# Generated by innovus_enablement/scripts/gen_fakeram.py: abstract 2048x39 SRAM.
# Geometry is an assumption (see script header), not PDK data.
VERSION 5.8 ;
BUSBITCHARS "[]" ;
DIVIDERCHAR "/" ;

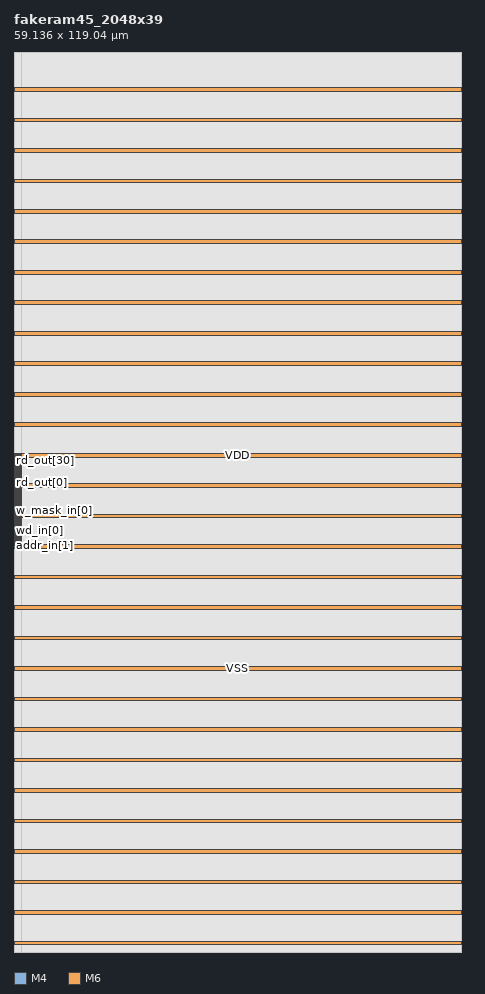
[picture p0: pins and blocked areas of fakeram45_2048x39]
MACRO fakeram45_2048x39
  CLASS BLOCK ;
  FOREIGN fakeram45_2048x39 0 0 ;
  ORIGIN 0 0 ;
  SIZE 59.1360 BY 119.0400 ;
  SYMMETRY X Y R90 ;
  PIN clk
    DIRECTION INPUT ;
    USE CLOCK ;
    PORT
      LAYER M4 ;
        RECT 0 53.3040 0.9600 53.3520 ;
    END
  END clk
  PIN ce_in
    DIRECTION INPUT ;
    USE SIGNAL ;
    PORT
      LAYER M4 ;
        RECT 0 53.4000 0.9600 53.4480 ;
    END
  END ce_in
  PIN we_in
    DIRECTION INPUT ;
    USE SIGNAL ;
    PORT
      LAYER M4 ;
        RECT 0 53.4960 0.9600 53.5440 ;
    END
  END we_in
  PIN addr_in[0]
    DIRECTION INPUT ;
    USE SIGNAL ;
    PORT
      LAYER M4 ;
        RECT 0 53.5920 0.9600 53.6400 ;
    END
  END addr_in[0]
  PIN addr_in[1]
    DIRECTION INPUT ;
    USE SIGNAL ;
    PORT
      LAYER M4 ;
        RECT 0 53.6880 0.9600 53.7360 ;
    END
  END addr_in[1]
  PIN addr_in[2]
    DIRECTION INPUT ;
    USE SIGNAL ;
    PORT
      LAYER M4 ;
        RECT 0 53.7840 0.9600 53.8320 ;
    END
  END addr_in[2]
  PIN addr_in[3]
    DIRECTION INPUT ;
    USE SIGNAL ;
    PORT
      LAYER M4 ;
        RECT 0 53.8800 0.9600 53.9280 ;
    END
  END addr_in[3]
  PIN addr_in[4]
    DIRECTION INPUT ;
    USE SIGNAL ;
    PORT
      LAYER M4 ;
        RECT 0 53.9760 0.9600 54.0240 ;
    END
  END addr_in[4]
  PIN addr_in[5]
    DIRECTION INPUT ;
    USE SIGNAL ;
    PORT
      LAYER M4 ;
        RECT 0 54.0720 0.9600 54.1200 ;
    END
  END addr_in[5]
  PIN addr_in[6]
    DIRECTION INPUT ;
    USE SIGNAL ;
    PORT
      LAYER M4 ;
        RECT 0 54.1680 0.9600 54.2160 ;
    END
  END addr_in[6]
  PIN addr_in[7]
    DIRECTION INPUT ;
    USE SIGNAL ;
    PORT
      LAYER M4 ;
        RECT 0 54.2640 0.9600 54.3120 ;
    END
  END addr_in[7]
  PIN addr_in[8]
    DIRECTION INPUT ;
    USE SIGNAL ;
    PORT
      LAYER M4 ;
        RECT 0 54.3600 0.9600 54.4080 ;
    END
  END addr_in[8]
  PIN addr_in[9]
    DIRECTION INPUT ;
    USE SIGNAL ;
    PORT
      LAYER M4 ;
        RECT 0 54.4560 0.9600 54.5040 ;
    END
  END addr_in[9]
  PIN addr_in[10]
    DIRECTION INPUT ;
    USE SIGNAL ;
    PORT
      LAYER M4 ;
        RECT 0 54.5520 0.9600 54.6000 ;
    END
  END addr_in[10]
  PIN wd_in[0]
    DIRECTION INPUT ;
    USE SIGNAL ;
    PORT
      LAYER M4 ;
        RECT 0 54.6480 0.9600 54.6960 ;
    END
  END wd_in[0]
  PIN wd_in[1]
    DIRECTION INPUT ;
    USE SIGNAL ;
    PORT
      LAYER M4 ;
        RECT 0 54.7440 0.9600 54.7920 ;
    END
  END wd_in[1]
  PIN wd_in[2]
    DIRECTION INPUT ;
    USE SIGNAL ;
    PORT
      LAYER M4 ;
        RECT 0 54.8400 0.9600 54.8880 ;
    END
  END wd_in[2]
  PIN wd_in[3]
    DIRECTION INPUT ;
    USE SIGNAL ;
    PORT
      LAYER M4 ;
        RECT 0 54.9360 0.9600 54.9840 ;
    END
  END wd_in[3]
  PIN wd_in[4]
    DIRECTION INPUT ;
    USE SIGNAL ;
    PORT
      LAYER M4 ;
        RECT 0 55.0320 0.9600 55.0800 ;
    END
  END wd_in[4]
  PIN wd_in[5]
    DIRECTION INPUT ;
    USE SIGNAL ;
    PORT
      LAYER M4 ;
        RECT 0 55.1280 0.9600 55.1760 ;
    END
  END wd_in[5]
  PIN wd_in[6]
    DIRECTION INPUT ;
    USE SIGNAL ;
    PORT
      LAYER M4 ;
        RECT 0 55.2240 0.9600 55.2720 ;
    END
  END wd_in[6]
  PIN wd_in[7]
    DIRECTION INPUT ;
    USE SIGNAL ;
    PORT
      LAYER M4 ;
        RECT 0 55.3200 0.9600 55.3680 ;
    END
  END wd_in[7]
  PIN wd_in[8]
    DIRECTION INPUT ;
    USE SIGNAL ;
    PORT
      LAYER M4 ;
        RECT 0 55.4160 0.9600 55.4640 ;
    END
  END wd_in[8]
  PIN wd_in[9]
    DIRECTION INPUT ;
    USE SIGNAL ;
    PORT
      LAYER M4 ;
        RECT 0 55.5120 0.9600 55.5600 ;
    END
  END wd_in[9]
  PIN wd_in[10]
    DIRECTION INPUT ;
    USE SIGNAL ;
    PORT
      LAYER M4 ;
        RECT 0 55.6080 0.9600 55.6560 ;
    END
  END wd_in[10]
  PIN wd_in[11]
    DIRECTION INPUT ;
    USE SIGNAL ;
    PORT
      LAYER M4 ;
        RECT 0 55.7040 0.9600 55.7520 ;
    END
  END wd_in[11]
  PIN wd_in[12]
    DIRECTION INPUT ;
    USE SIGNAL ;
    PORT
      LAYER M4 ;
        RECT 0 55.8000 0.9600 55.8480 ;
    END
  END wd_in[12]
  PIN wd_in[13]
    DIRECTION INPUT ;
    USE SIGNAL ;
    PORT
      LAYER M4 ;
        RECT 0 55.8960 0.9600 55.9440 ;
    END
  END wd_in[13]
  PIN wd_in[14]
    DIRECTION INPUT ;
    USE SIGNAL ;
    PORT
      LAYER M4 ;
        RECT 0 55.9920 0.9600 56.0400 ;
    END
  END wd_in[14]
  PIN wd_in[15]
    DIRECTION INPUT ;
    USE SIGNAL ;
    PORT
      LAYER M4 ;
        RECT 0 56.0880 0.9600 56.1360 ;
    END
  END wd_in[15]
  PIN wd_in[16]
    DIRECTION INPUT ;
    USE SIGNAL ;
    PORT
      LAYER M4 ;
        RECT 0 56.1840 0.9600 56.2320 ;
    END
  END wd_in[16]
  PIN wd_in[17]
    DIRECTION INPUT ;
    USE SIGNAL ;
    PORT
      LAYER M4 ;
        RECT 0 56.2800 0.9600 56.3280 ;
    END
  END wd_in[17]
  PIN wd_in[18]
    DIRECTION INPUT ;
    USE SIGNAL ;
    PORT
      LAYER M4 ;
        RECT 0 56.3760 0.9600 56.4240 ;
    END
  END wd_in[18]
  PIN wd_in[19]
    DIRECTION INPUT ;
    USE SIGNAL ;
    PORT
      LAYER M4 ;
        RECT 0 56.4720 0.9600 56.5200 ;
    END
  END wd_in[19]
  PIN wd_in[20]
    DIRECTION INPUT ;
    USE SIGNAL ;
    PORT
      LAYER M4 ;
        RECT 0 56.5680 0.9600 56.6160 ;
    END
  END wd_in[20]
  PIN wd_in[21]
    DIRECTION INPUT ;
    USE SIGNAL ;
    PORT
      LAYER M4 ;
        RECT 0 56.6640 0.9600 56.7120 ;
    END
  END wd_in[21]
  PIN wd_in[22]
    DIRECTION INPUT ;
    USE SIGNAL ;
    PORT
      LAYER M4 ;
        RECT 0 56.7600 0.9600 56.8080 ;
    END
  END wd_in[22]
  PIN wd_in[23]
    DIRECTION INPUT ;
    USE SIGNAL ;
    PORT
      LAYER M4 ;
        RECT 0 56.8560 0.9600 56.9040 ;
    END
  END wd_in[23]
  PIN wd_in[24]
    DIRECTION INPUT ;
    USE SIGNAL ;
    PORT
      LAYER M4 ;
        RECT 0 56.9520 0.9600 57.0000 ;
    END
  END wd_in[24]
  PIN wd_in[25]
    DIRECTION INPUT ;
    USE SIGNAL ;
    PORT
      LAYER M4 ;
        RECT 0 57.0480 0.9600 57.0960 ;
    END
  END wd_in[25]
  PIN wd_in[26]
    DIRECTION INPUT ;
    USE SIGNAL ;
    PORT
      LAYER M4 ;
        RECT 0 57.1440 0.9600 57.1920 ;
    END
  END wd_in[26]
  PIN wd_in[27]
    DIRECTION INPUT ;
    USE SIGNAL ;
    PORT
      LAYER M4 ;
        RECT 0 57.2400 0.9600 57.2880 ;
    END
  END wd_in[27]
  PIN wd_in[28]
    DIRECTION INPUT ;
    USE SIGNAL ;
    PORT
      LAYER M4 ;
        RECT 0 57.3360 0.9600 57.3840 ;
    END
  END wd_in[28]
  PIN wd_in[29]
    DIRECTION INPUT ;
    USE SIGNAL ;
    PORT
      LAYER M4 ;
        RECT 0 57.4320 0.9600 57.4800 ;
    END
  END wd_in[29]
  PIN wd_in[30]
    DIRECTION INPUT ;
    USE SIGNAL ;
    PORT
      LAYER M4 ;
        RECT 0 57.5280 0.9600 57.5760 ;
    END
  END wd_in[30]
  PIN wd_in[31]
    DIRECTION INPUT ;
    USE SIGNAL ;
    PORT
      LAYER M4 ;
        RECT 0 57.6240 0.9600 57.6720 ;
    END
  END wd_in[31]
  PIN wd_in[32]
    DIRECTION INPUT ;
    USE SIGNAL ;
    PORT
      LAYER M4 ;
        RECT 0 57.7200 0.9600 57.7680 ;
    END
  END wd_in[32]
  PIN wd_in[33]
    DIRECTION INPUT ;
    USE SIGNAL ;
    PORT
      LAYER M4 ;
        RECT 0 57.8160 0.9600 57.8640 ;
    END
  END wd_in[33]
  PIN wd_in[34]
    DIRECTION INPUT ;
    USE SIGNAL ;
    PORT
      LAYER M4 ;
        RECT 0 57.9120 0.9600 57.9600 ;
    END
  END wd_in[34]
  PIN wd_in[35]
    DIRECTION INPUT ;
    USE SIGNAL ;
    PORT
      LAYER M4 ;
        RECT 0 58.0080 0.9600 58.0560 ;
    END
  END wd_in[35]
  PIN wd_in[36]
    DIRECTION INPUT ;
    USE SIGNAL ;
    PORT
      LAYER M4 ;
        RECT 0 58.1040 0.9600 58.1520 ;
    END
  END wd_in[36]
  PIN wd_in[37]
    DIRECTION INPUT ;
    USE SIGNAL ;
    PORT
      LAYER M4 ;
        RECT 0 58.2000 0.9600 58.2480 ;
    END
  END wd_in[37]
  PIN wd_in[38]
    DIRECTION INPUT ;
    USE SIGNAL ;
    PORT
      LAYER M4 ;
        RECT 0 58.2960 0.9600 58.3440 ;
    END
  END wd_in[38]
  PIN w_mask_in[0]
    DIRECTION INPUT ;
    USE SIGNAL ;
    PORT
      LAYER M4 ;
        RECT 0 58.3920 0.9600 58.4400 ;
    END
  END w_mask_in[0]
  PIN w_mask_in[1]
    DIRECTION INPUT ;
    USE SIGNAL ;
    PORT
      LAYER M4 ;
        RECT 0 58.4880 0.9600 58.5360 ;
    END
  END w_mask_in[1]
  PIN w_mask_in[2]
    DIRECTION INPUT ;
    USE SIGNAL ;
    PORT
      LAYER M4 ;
        RECT 0 58.5840 0.9600 58.6320 ;
    END
  END w_mask_in[2]
  PIN w_mask_in[3]
    DIRECTION INPUT ;
    USE SIGNAL ;
    PORT
      LAYER M4 ;
        RECT 0 58.6800 0.9600 58.7280 ;
    END
  END w_mask_in[3]
  PIN w_mask_in[4]
    DIRECTION INPUT ;
    USE SIGNAL ;
    PORT
      LAYER M4 ;
        RECT 0 58.7760 0.9600 58.8240 ;
    END
  END w_mask_in[4]
  PIN w_mask_in[5]
    DIRECTION INPUT ;
    USE SIGNAL ;
    PORT
      LAYER M4 ;
        RECT 0 58.8720 0.9600 58.9200 ;
    END
  END w_mask_in[5]
  PIN w_mask_in[6]
    DIRECTION INPUT ;
    USE SIGNAL ;
    PORT
      LAYER M4 ;
        RECT 0 58.9680 0.9600 59.0160 ;
    END
  END w_mask_in[6]
  PIN w_mask_in[7]
    DIRECTION INPUT ;
    USE SIGNAL ;
    PORT
      LAYER M4 ;
        RECT 0 59.0640 0.9600 59.1120 ;
    END
  END w_mask_in[7]
  PIN w_mask_in[8]
    DIRECTION INPUT ;
    USE SIGNAL ;
    PORT
      LAYER M4 ;
        RECT 0 59.1600 0.9600 59.2080 ;
    END
  END w_mask_in[8]
  PIN w_mask_in[9]
    DIRECTION INPUT ;
    USE SIGNAL ;
    PORT
      LAYER M4 ;
        RECT 0 59.2560 0.9600 59.3040 ;
    END
  END w_mask_in[9]
  PIN w_mask_in[10]
    DIRECTION INPUT ;
    USE SIGNAL ;
    PORT
      LAYER M4 ;
        RECT 0 59.3520 0.9600 59.4000 ;
    END
  END w_mask_in[10]
  PIN w_mask_in[11]
    DIRECTION INPUT ;
    USE SIGNAL ;
    PORT
      LAYER M4 ;
        RECT 0 59.4480 0.9600 59.4960 ;
    END
  END w_mask_in[11]
  PIN w_mask_in[12]
    DIRECTION INPUT ;
    USE SIGNAL ;
    PORT
      LAYER M4 ;
        RECT 0 59.5440 0.9600 59.5920 ;
    END
  END w_mask_in[12]
  PIN w_mask_in[13]
    DIRECTION INPUT ;
    USE SIGNAL ;
    PORT
      LAYER M4 ;
        RECT 0 59.6400 0.9600 59.6880 ;
    END
  END w_mask_in[13]
  PIN w_mask_in[14]
    DIRECTION INPUT ;
    USE SIGNAL ;
    PORT
      LAYER M4 ;
        RECT 0 59.7360 0.9600 59.7840 ;
    END
  END w_mask_in[14]
  PIN w_mask_in[15]
    DIRECTION INPUT ;
    USE SIGNAL ;
    PORT
      LAYER M4 ;
        RECT 0 59.8320 0.9600 59.8800 ;
    END
  END w_mask_in[15]
  PIN w_mask_in[16]
    DIRECTION INPUT ;
    USE SIGNAL ;
    PORT
      LAYER M4 ;
        RECT 0 59.9280 0.9600 59.9760 ;
    END
  END w_mask_in[16]
  PIN w_mask_in[17]
    DIRECTION INPUT ;
    USE SIGNAL ;
    PORT
      LAYER M4 ;
        RECT 0 60.0240 0.9600 60.0720 ;
    END
  END w_mask_in[17]
  PIN w_mask_in[18]
    DIRECTION INPUT ;
    USE SIGNAL ;
    PORT
      LAYER M4 ;
        RECT 0 60.1200 0.9600 60.1680 ;
    END
  END w_mask_in[18]
  PIN w_mask_in[19]
    DIRECTION INPUT ;
    USE SIGNAL ;
    PORT
      LAYER M4 ;
        RECT 0 60.2160 0.9600 60.2640 ;
    END
  END w_mask_in[19]
  PIN w_mask_in[20]
    DIRECTION INPUT ;
    USE SIGNAL ;
    PORT
      LAYER M4 ;
        RECT 0 60.3120 0.9600 60.3600 ;
    END
  END w_mask_in[20]
  PIN w_mask_in[21]
    DIRECTION INPUT ;
    USE SIGNAL ;
    PORT
      LAYER M4 ;
        RECT 0 60.4080 0.9600 60.4560 ;
    END
  END w_mask_in[21]
  PIN w_mask_in[22]
    DIRECTION INPUT ;
    USE SIGNAL ;
    PORT
      LAYER M4 ;
        RECT 0 60.5040 0.9600 60.5520 ;
    END
  END w_mask_in[22]
  PIN w_mask_in[23]
    DIRECTION INPUT ;
    USE SIGNAL ;
    PORT
      LAYER M4 ;
        RECT 0 60.6000 0.9600 60.6480 ;
    END
  END w_mask_in[23]
  PIN w_mask_in[24]
    DIRECTION INPUT ;
    USE SIGNAL ;
    PORT
      LAYER M4 ;
        RECT 0 60.6960 0.9600 60.7440 ;
    END
  END w_mask_in[24]
  PIN w_mask_in[25]
    DIRECTION INPUT ;
    USE SIGNAL ;
    PORT
      LAYER M4 ;
        RECT 0 60.7920 0.9600 60.8400 ;
    END
  END w_mask_in[25]
  PIN w_mask_in[26]
    DIRECTION INPUT ;
    USE SIGNAL ;
    PORT
      LAYER M4 ;
        RECT 0 60.8880 0.9600 60.9360 ;
    END
  END w_mask_in[26]
  PIN w_mask_in[27]
    DIRECTION INPUT ;
    USE SIGNAL ;
    PORT
      LAYER M4 ;
        RECT 0 60.9840 0.9600 61.0320 ;
    END
  END w_mask_in[27]
  PIN w_mask_in[28]
    DIRECTION INPUT ;
    USE SIGNAL ;
    PORT
      LAYER M4 ;
        RECT 0 61.0800 0.9600 61.1280 ;
    END
  END w_mask_in[28]
  PIN w_mask_in[29]
    DIRECTION INPUT ;
    USE SIGNAL ;
    PORT
      LAYER M4 ;
        RECT 0 61.1760 0.9600 61.2240 ;
    END
  END w_mask_in[29]
  PIN w_mask_in[30]
    DIRECTION INPUT ;
    USE SIGNAL ;
    PORT
      LAYER M4 ;
        RECT 0 61.2720 0.9600 61.3200 ;
    END
  END w_mask_in[30]
  PIN w_mask_in[31]
    DIRECTION INPUT ;
    USE SIGNAL ;
    PORT
      LAYER M4 ;
        RECT 0 61.3680 0.9600 61.4160 ;
    END
  END w_mask_in[31]
  PIN w_mask_in[32]
    DIRECTION INPUT ;
    USE SIGNAL ;
    PORT
      LAYER M4 ;
        RECT 0 61.4640 0.9600 61.5120 ;
    END
  END w_mask_in[32]
  PIN w_mask_in[33]
    DIRECTION INPUT ;
    USE SIGNAL ;
    PORT
      LAYER M4 ;
        RECT 0 61.5600 0.9600 61.6080 ;
    END
  END w_mask_in[33]
  PIN w_mask_in[34]
    DIRECTION INPUT ;
    USE SIGNAL ;
    PORT
      LAYER M4 ;
        RECT 0 61.6560 0.9600 61.7040 ;
    END
  END w_mask_in[34]
  PIN w_mask_in[35]
    DIRECTION INPUT ;
    USE SIGNAL ;
    PORT
      LAYER M4 ;
        RECT 0 61.7520 0.9600 61.8000 ;
    END
  END w_mask_in[35]
  PIN w_mask_in[36]
    DIRECTION INPUT ;
    USE SIGNAL ;
    PORT
      LAYER M4 ;
        RECT 0 61.8480 0.9600 61.8960 ;
    END
  END w_mask_in[36]
  PIN w_mask_in[37]
    DIRECTION INPUT ;
    USE SIGNAL ;
    PORT
      LAYER M4 ;
        RECT 0 61.9440 0.9600 61.9920 ;
    END
  END w_mask_in[37]
  PIN w_mask_in[38]
    DIRECTION INPUT ;
    USE SIGNAL ;
    PORT
      LAYER M4 ;
        RECT 0 62.0400 0.9600 62.0880 ;
    END
  END w_mask_in[38]
  PIN rd_out[0]
    DIRECTION OUTPUT ;
    USE SIGNAL ;
    PORT
      LAYER M4 ;
        RECT 0 62.1360 0.9600 62.1840 ;
    END
  END rd_out[0]
  PIN rd_out[1]
    DIRECTION OUTPUT ;
    USE SIGNAL ;
    PORT
      LAYER M4 ;
        RECT 0 62.2320 0.9600 62.2800 ;
    END
  END rd_out[1]
  PIN rd_out[2]
    DIRECTION OUTPUT ;
    USE SIGNAL ;
    PORT
      LAYER M4 ;
        RECT 0 62.3280 0.9600 62.3760 ;
    END
  END rd_out[2]
  PIN rd_out[3]
    DIRECTION OUTPUT ;
    USE SIGNAL ;
    PORT
      LAYER M4 ;
        RECT 0 62.4240 0.9600 62.4720 ;
    END
  END rd_out[3]
  PIN rd_out[4]
    DIRECTION OUTPUT ;
    USE SIGNAL ;
    PORT
      LAYER M4 ;
        RECT 0 62.5200 0.9600 62.5680 ;
    END
  END rd_out[4]
  PIN rd_out[5]
    DIRECTION OUTPUT ;
    USE SIGNAL ;
    PORT
      LAYER M4 ;
        RECT 0 62.6160 0.9600 62.6640 ;
    END
  END rd_out[5]
  PIN rd_out[6]
    DIRECTION OUTPUT ;
    USE SIGNAL ;
    PORT
      LAYER M4 ;
        RECT 0 62.7120 0.9600 62.7600 ;
    END
  END rd_out[6]
  PIN rd_out[7]
    DIRECTION OUTPUT ;
    USE SIGNAL ;
    PORT
      LAYER M4 ;
        RECT 0 62.8080 0.9600 62.8560 ;
    END
  END rd_out[7]
  PIN rd_out[8]
    DIRECTION OUTPUT ;
    USE SIGNAL ;
    PORT
      LAYER M4 ;
        RECT 0 62.9040 0.9600 62.9520 ;
    END
  END rd_out[8]
  PIN rd_out[9]
    DIRECTION OUTPUT ;
    USE SIGNAL ;
    PORT
      LAYER M4 ;
        RECT 0 63.0000 0.9600 63.0480 ;
    END
  END rd_out[9]
  PIN rd_out[10]
    DIRECTION OUTPUT ;
    USE SIGNAL ;
    PORT
      LAYER M4 ;
        RECT 0 63.0960 0.9600 63.1440 ;
    END
  END rd_out[10]
  PIN rd_out[11]
    DIRECTION OUTPUT ;
    USE SIGNAL ;
    PORT
      LAYER M4 ;
        RECT 0 63.1920 0.9600 63.2400 ;
    END
  END rd_out[11]
  PIN rd_out[12]
    DIRECTION OUTPUT ;
    USE SIGNAL ;
    PORT
      LAYER M4 ;
        RECT 0 63.2880 0.9600 63.3360 ;
    END
  END rd_out[12]
  PIN rd_out[13]
    DIRECTION OUTPUT ;
    USE SIGNAL ;
    PORT
      LAYER M4 ;
        RECT 0 63.3840 0.9600 63.4320 ;
    END
  END rd_out[13]
  PIN rd_out[14]
    DIRECTION OUTPUT ;
    USE SIGNAL ;
    PORT
      LAYER M4 ;
        RECT 0 63.4800 0.9600 63.5280 ;
    END
  END rd_out[14]
  PIN rd_out[15]
    DIRECTION OUTPUT ;
    USE SIGNAL ;
    PORT
      LAYER M4 ;
        RECT 0 63.5760 0.9600 63.6240 ;
    END
  END rd_out[15]
  PIN rd_out[16]
    DIRECTION OUTPUT ;
    USE SIGNAL ;
    PORT
      LAYER M4 ;
        RECT 0 63.6720 0.9600 63.7200 ;
    END
  END rd_out[16]
  PIN rd_out[17]
    DIRECTION OUTPUT ;
    USE SIGNAL ;
    PORT
      LAYER M4 ;
        RECT 0 63.7680 0.9600 63.8160 ;
    END
  END rd_out[17]
  PIN rd_out[18]
    DIRECTION OUTPUT ;
    USE SIGNAL ;
    PORT
      LAYER M4 ;
        RECT 0 63.8640 0.9600 63.9120 ;
    END
  END rd_out[18]
  PIN rd_out[19]
    DIRECTION OUTPUT ;
    USE SIGNAL ;
    PORT
      LAYER M4 ;
        RECT 0 63.9600 0.9600 64.0080 ;
    END
  END rd_out[19]
  PIN rd_out[20]
    DIRECTION OUTPUT ;
    USE SIGNAL ;
    PORT
      LAYER M4 ;
        RECT 0 64.0560 0.9600 64.1040 ;
    END
  END rd_out[20]
  PIN rd_out[21]
    DIRECTION OUTPUT ;
    USE SIGNAL ;
    PORT
      LAYER M4 ;
        RECT 0 64.1520 0.9600 64.2000 ;
    END
  END rd_out[21]
  PIN rd_out[22]
    DIRECTION OUTPUT ;
    USE SIGNAL ;
    PORT
      LAYER M4 ;
        RECT 0 64.2480 0.9600 64.2960 ;
    END
  END rd_out[22]
  PIN rd_out[23]
    DIRECTION OUTPUT ;
    USE SIGNAL ;
    PORT
      LAYER M4 ;
        RECT 0 64.3440 0.9600 64.3920 ;
    END
  END rd_out[23]
  PIN rd_out[24]
    DIRECTION OUTPUT ;
    USE SIGNAL ;
    PORT
      LAYER M4 ;
        RECT 0 64.4400 0.9600 64.4880 ;
    END
  END rd_out[24]
  PIN rd_out[25]
    DIRECTION OUTPUT ;
    USE SIGNAL ;
    PORT
      LAYER M4 ;
        RECT 0 64.5360 0.9600 64.5840 ;
    END
  END rd_out[25]
  PIN rd_out[26]
    DIRECTION OUTPUT ;
    USE SIGNAL ;
    PORT
      LAYER M4 ;
        RECT 0 64.6320 0.9600 64.6800 ;
    END
  END rd_out[26]
  PIN rd_out[27]
    DIRECTION OUTPUT ;
    USE SIGNAL ;
    PORT
      LAYER M4 ;
        RECT 0 64.7280 0.9600 64.7760 ;
    END
  END rd_out[27]
  PIN rd_out[28]
    DIRECTION OUTPUT ;
    USE SIGNAL ;
    PORT
      LAYER M4 ;
        RECT 0 64.8240 0.9600 64.8720 ;
    END
  END rd_out[28]
  PIN rd_out[29]
    DIRECTION OUTPUT ;
    USE SIGNAL ;
    PORT
      LAYER M4 ;
        RECT 0 64.9200 0.9600 64.9680 ;
    END
  END rd_out[29]
  PIN rd_out[30]
    DIRECTION OUTPUT ;
    USE SIGNAL ;
    PORT
      LAYER M4 ;
        RECT 0 65.0160 0.9600 65.0640 ;
    END
  END rd_out[30]
  PIN rd_out[31]
    DIRECTION OUTPUT ;
    USE SIGNAL ;
    PORT
      LAYER M4 ;
        RECT 0 65.1120 0.9600 65.1600 ;
    END
  END rd_out[31]
  PIN rd_out[32]
    DIRECTION OUTPUT ;
    USE SIGNAL ;
    PORT
      LAYER M4 ;
        RECT 0 65.2080 0.9600 65.2560 ;
    END
  END rd_out[32]
  PIN rd_out[33]
    DIRECTION OUTPUT ;
    USE SIGNAL ;
    PORT
      LAYER M4 ;
        RECT 0 65.3040 0.9600 65.3520 ;
    END
  END rd_out[33]
  PIN rd_out[34]
    DIRECTION OUTPUT ;
    USE SIGNAL ;
    PORT
      LAYER M4 ;
        RECT 0 65.4000 0.9600 65.4480 ;
    END
  END rd_out[34]
  PIN rd_out[35]
    DIRECTION OUTPUT ;
    USE SIGNAL ;
    PORT
      LAYER M4 ;
        RECT 0 65.4960 0.9600 65.5440 ;
    END
  END rd_out[35]
  PIN rd_out[36]
    DIRECTION OUTPUT ;
    USE SIGNAL ;
    PORT
      LAYER M4 ;
        RECT 0 65.5920 0.9600 65.6400 ;
    END
  END rd_out[36]
  PIN rd_out[37]
    DIRECTION OUTPUT ;
    USE SIGNAL ;
    PORT
      LAYER M4 ;
        RECT 0 65.6880 0.9600 65.7360 ;
    END
  END rd_out[37]
  PIN rd_out[38]
    DIRECTION OUTPUT ;
    USE SIGNAL ;
    PORT
      LAYER M4 ;
        RECT 0 65.7840 0.9600 65.8320 ;
    END
  END rd_out[38]
  PIN VDD
    DIRECTION INOUT ;
    USE POWER ;
    PORT
      LAYER M6 ;
        RECT 0 0.9600 59.1360 1.4400 ;
        RECT 0 9.0240 59.1360 9.5040 ;
        RECT 0 17.0880 59.1360 17.5680 ;
        RECT 0 25.1520 59.1360 25.6320 ;
        RECT 0 33.2160 59.1360 33.6960 ;
        RECT 0 41.2800 59.1360 41.7600 ;
        RECT 0 49.3440 59.1360 49.8240 ;
        RECT 0 57.4080 59.1360 57.8880 ;
        RECT 0 65.4720 59.1360 65.9520 ;
        RECT 0 73.5360 59.1360 74.0160 ;
        RECT 0 81.6000 59.1360 82.0800 ;
        RECT 0 89.6640 59.1360 90.1440 ;
        RECT 0 97.7280 59.1360 98.2080 ;
        RECT 0 105.7920 59.1360 106.2720 ;
        RECT 0 113.8560 59.1360 114.3360 ;
    END
  END VDD
  PIN VSS
    DIRECTION INOUT ;
    USE GROUND ;
    PORT
      LAYER M6 ;
        RECT 0 4.9920 59.1360 5.4720 ;
        RECT 0 13.0560 59.1360 13.5360 ;
        RECT 0 21.1200 59.1360 21.6000 ;
        RECT 0 29.1840 59.1360 29.6640 ;
        RECT 0 37.2480 59.1360 37.7280 ;
        RECT 0 45.3120 59.1360 45.7920 ;
        RECT 0 53.3760 59.1360 53.8560 ;
        RECT 0 61.4400 59.1360 61.9200 ;
        RECT 0 69.5040 59.1360 69.9840 ;
        RECT 0 77.5680 59.1360 78.0480 ;
        RECT 0 85.6320 59.1360 86.1120 ;
        RECT 0 93.6960 59.1360 94.1760 ;
        RECT 0 101.7600 59.1360 102.2400 ;
        RECT 0 109.8240 59.1360 110.3040 ;
    END
  END VSS
  OBS
    LAYER M0 ;
      RECT 0 0 59.1360 119.0400 ;
    LAYER M1 ;
      RECT 0 0 59.1360 119.0400 ;
    LAYER M2 ;
      RECT 0 0 59.1360 119.0400 ;
    LAYER M3 ;
      RECT 0 0 59.1360 119.0400 ;
    LAYER VIA0 ;
      RECT 0 0 59.1360 119.0400 ;
    LAYER VIA1 ;
      RECT 0 0 59.1360 119.0400 ;
    LAYER VIA2 ;
      RECT 0 0 59.1360 119.0400 ;
    LAYER VIA3 ;
      RECT 0 0 59.1360 119.0400 ;
    LAYER M4 ;
      RECT 1.0560 0 59.1360 119.0400 ;
  END
END fakeram45_2048x39

END LIBRARY
